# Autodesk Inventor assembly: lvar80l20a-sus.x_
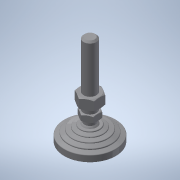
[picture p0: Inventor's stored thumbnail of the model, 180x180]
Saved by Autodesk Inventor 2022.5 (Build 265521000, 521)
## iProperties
Part Number: lvar80l20a-sus.x_
Material: 一般
Document SubType Name: Assembly
Designer: ImaoCorp
Sending System: SOLIDWORKS 2017-2017317
MC: AMD64
MC_MODEL: Intel64 Family 6 Model 60 Stepping 3, GenuineIntel
OS: Windows_NT
FRU: Parasolid Version 29.0, build 201,  4-17-2017
FORMAT: text
GUISE: transmit
KEY: lvar80l20a-sus
FILE: lvar80l20a-sus.x_t
DATE: Mon Jul 01 18:14:51 2019
Author: ImaoCorp
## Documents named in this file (3)
- X:\14_SW2022-Inv2022\00_全2023-1023新製品(TCC)まで\l\lvar80l20a-sus\LVAR80L20A-SUS.iam
- X:\14_SW2022-Inv2022\00_全2023-1023新製品(TCC)まで\l\lvar80l20a-sus\lvar80l20a-sus_01.ipt
- X:\14_SW2022-Inv2022\00_全2023-1023新製品(TCC)まで\l\lvar80l20a-sus\lvar80l20a-sus_02.ipt
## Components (2 placed, 2 different names)
1. lvar80l20a-sus_01
2. lvar80l20a-sus_02
